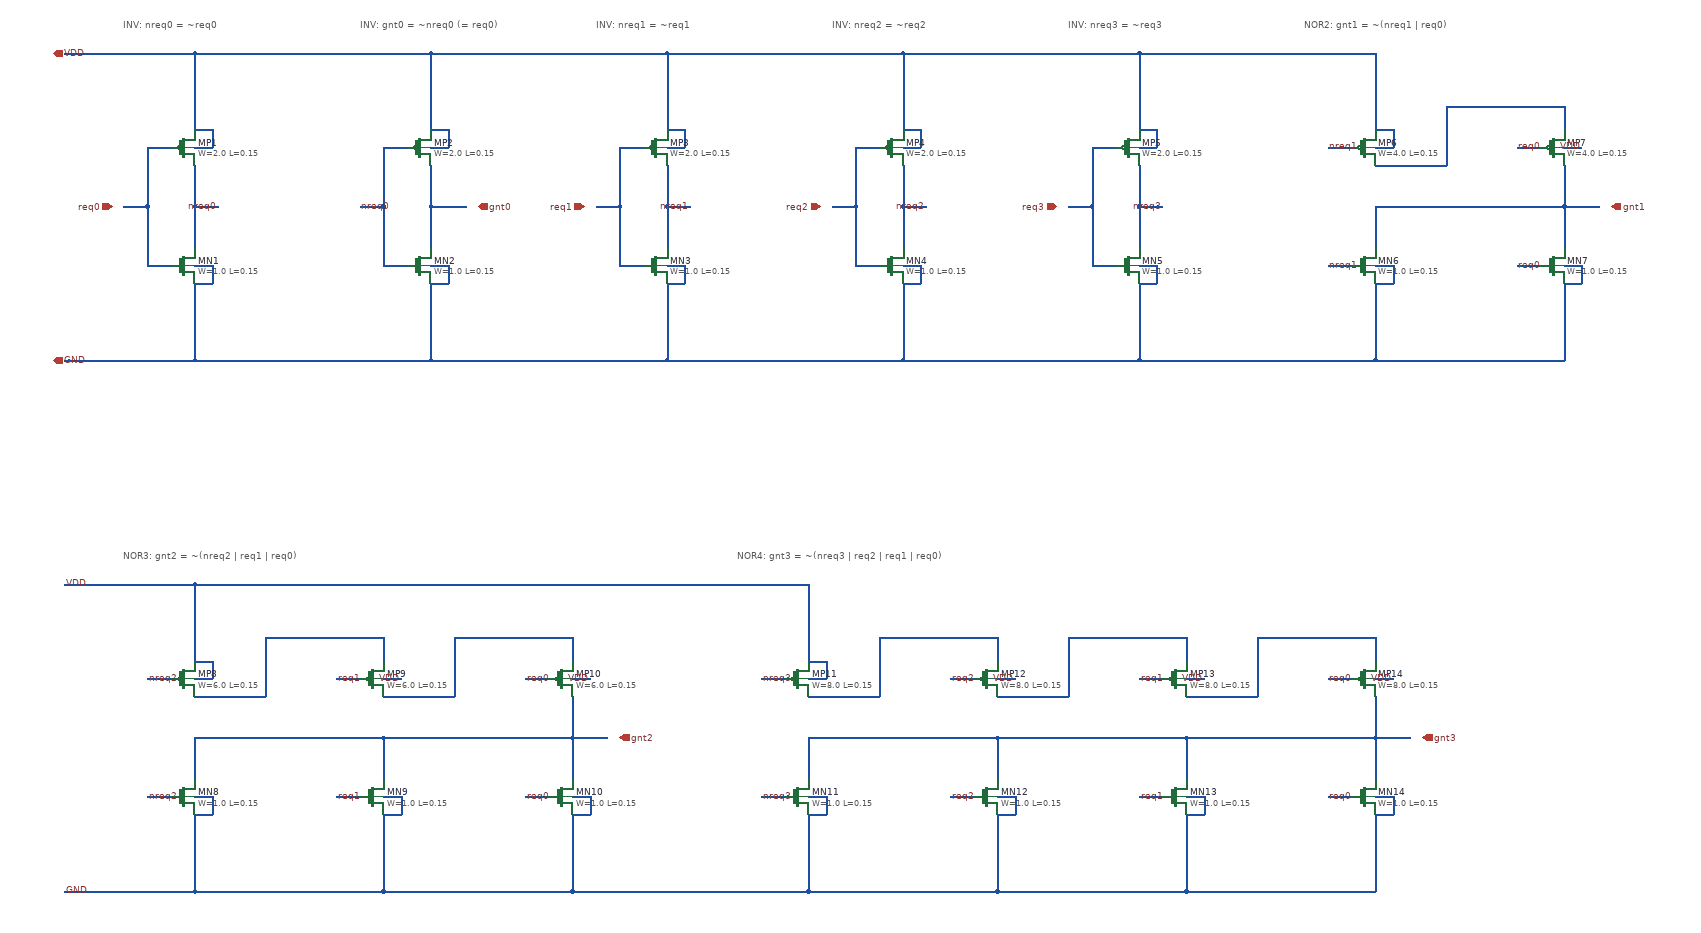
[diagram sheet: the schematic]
v {xschem version=3.4.5 file_version=1.2
}
G {}
K {}
V {}
S {}
E {}
N 180 -100 140 -100 {}
N 180 100 140 100 {}
N 140 -100 140 0 {}
N 140 0 140 100 {}
N 140 0 100 0 {}
N 220 -100 250 -100 {}
N 250 -100 250 -130 {}
N 250 -130 220 -130 {}
N 220 -130 220 -260 {}
N 220 -70 220 0 {}
N 220 100 250 100 {}
N 250 100 250 130 {}
N 250 130 220 130 {}
N 220 130 220 260 {}
N 220 70 220 0 {}
N 220 0 260 0 {}
N 580 -100 540 -100 {}
N 580 100 540 100 {}
N 540 -100 540 0 {}
N 540 0 540 100 {}
N 540 0 500 0 {}
N 620 -100 650 -100 {}
N 650 -100 650 -130 {}
N 650 -130 620 -130 {}
N 620 -130 620 -260 {}
N 620 -70 620 0 {}
N 620 100 650 100 {}
N 650 100 650 130 {}
N 650 130 620 130 {}
N 620 130 620 260 {}
N 620 70 620 0 {}
N 620 0 680 0 {}
N 980 -100 940 -100 {}
N 980 100 940 100 {}
N 940 -100 940 0 {}
N 940 0 940 100 {}
N 940 0 900 0 {}
N 1020 -100 1050 -100 {}
N 1050 -100 1050 -130 {}
N 1050 -130 1020 -130 {}
N 1020 -130 1020 -260 {}
N 1020 -70 1020 0 {}
N 1020 100 1050 100 {}
N 1050 100 1050 130 {}
N 1050 130 1020 130 {}
N 1020 130 1020 260 {}
N 1020 70 1020 0 {}
N 1020 0 1060 0 {}
N 1380 -100 1340 -100 {}
N 1380 100 1340 100 {}
N 1340 -100 1340 0 {}
N 1340 0 1340 100 {}
N 1340 0 1300 0 {}
N 1420 -100 1450 -100 {}
N 1450 -100 1450 -130 {}
N 1450 -130 1420 -130 {}
N 1420 -130 1420 -260 {}
N 1420 -70 1420 0 {}
N 1420 100 1450 100 {}
N 1450 100 1450 130 {}
N 1450 130 1420 130 {}
N 1420 130 1420 260 {}
N 1420 70 1420 0 {}
N 1420 0 1460 0 {}
N 1780 -100 1740 -100 {}
N 1780 100 1740 100 {}
N 1740 -100 1740 0 {}
N 1740 0 1740 100 {}
N 1740 0 1700 0 {}
N 1820 -100 1850 -100 {}
N 1850 -100 1850 -130 {}
N 1850 -130 1820 -130 {}
N 1820 -130 1820 -260 {}
N 1820 -70 1820 0 {}
N 1820 100 1850 100 {}
N 1850 100 1850 130 {}
N 1850 130 1820 130 {}
N 1820 130 1820 260 {}
N 1820 70 1820 0 {}
N 1820 0 1860 0 {}
N 2180 -100 2140 -100 {}
N 2180 100 2140 100 {}
N 2220 -100 2250 -100 {}
N 2250 -100 2250 -130 {}
N 2250 -130 2220 -130 {}
N 2220 -130 2220 -260 {}
N 2220 -70 2340 -70 {}
N 2340 -70 2340 -170 {}
N 2340 -170 2540 -170 {}
N 2540 -170 2540 -130 {}
N 2220 100 2250 100 {}
N 2250 100 2250 130 {}
N 2250 130 2220 130 {}
N 2220 130 2220 260 {}
N 2220 70 2220 0 {}
N 2500 -100 2460 -100 {}
N 2500 100 2460 100 {}
N 2540 -100 2570 -100 {}
N 2540 -70 2540 0 {}
N 2540 100 2570 100 {}
N 2570 100 2570 130 {}
N 2570 130 2540 130 {}
N 2540 130 2540 260 {}
N 2540 70 2540 0 {}
N 2220 0 2540 0 {}
N 2540 0 2600 0 {}
N 180 800 140 800 {}
N 180 1000 140 1000 {}
N 220 800 250 800 {}
N 250 800 250 770 {}
N 250 770 220 770 {}
N 220 770 220 640 {}
N 220 830 340 830 {}
N 340 830 340 730 {}
N 340 730 540 730 {}
N 540 730 540 770 {}
N 220 1000 250 1000 {}
N 250 1000 250 1030 {}
N 250 1030 220 1030 {}
N 220 1030 220 1160 {}
N 220 970 220 900 {}
N 500 800 460 800 {}
N 500 1000 460 1000 {}
N 540 800 570 800 {}
N 540 830 660 830 {}
N 660 830 660 730 {}
N 660 730 860 730 {}
N 860 730 860 770 {}
N 540 1000 570 1000 {}
N 570 1000 570 1030 {}
N 570 1030 540 1030 {}
N 540 1030 540 1160 {}
N 540 970 540 900 {}
N 220 900 540 900 {}
N 820 800 780 800 {}
N 820 1000 780 1000 {}
N 860 800 890 800 {}
N 860 830 860 900 {}
N 860 1000 890 1000 {}
N 890 1000 890 1030 {}
N 890 1030 860 1030 {}
N 860 1030 860 1160 {}
N 860 970 860 900 {}
N 540 900 860 900 {}
N 860 900 920 900 {}
N 1220 800 1180 800 {}
N 1220 1000 1180 1000 {}
N 1260 800 1290 800 {}
N 1290 800 1290 770 {}
N 1290 770 1260 770 {}
N 1260 770 1260 640 {}
N 1260 830 1380 830 {}
N 1380 830 1380 730 {}
N 1380 730 1580 730 {}
N 1580 730 1580 770 {}
N 1260 1000 1290 1000 {}
N 1290 1000 1290 1030 {}
N 1290 1030 1260 1030 {}
N 1260 1030 1260 1160 {}
N 1260 970 1260 900 {}
N 1540 800 1500 800 {}
N 1540 1000 1500 1000 {}
N 1580 800 1610 800 {}
N 1580 830 1700 830 {}
N 1700 830 1700 730 {}
N 1700 730 1900 730 {}
N 1900 730 1900 770 {}
N 1580 1000 1610 1000 {}
N 1610 1000 1610 1030 {}
N 1610 1030 1580 1030 {}
N 1580 1030 1580 1160 {}
N 1580 970 1580 900 {}
N 1260 900 1580 900 {}
N 1860 800 1820 800 {}
N 1860 1000 1820 1000 {}
N 1900 800 1930 800 {}
N 1900 830 2020 830 {}
N 2020 830 2020 730 {}
N 2020 730 2220 730 {}
N 2220 730 2220 770 {}
N 1900 1000 1930 1000 {}
N 1930 1000 1930 1030 {}
N 1930 1030 1900 1030 {}
N 1900 1030 1900 1160 {}
N 1900 970 1900 900 {}
N 1580 900 1900 900 {}
N 2180 800 2140 800 {}
N 2180 1000 2140 1000 {}
N 2220 800 2250 800 {}
N 2220 830 2220 900 {}
N 2220 1000 2250 1000 {}
N 2250 1000 2250 1030 {}
N 2250 1030 2220 1030 {}
N 2220 1030 2220 1160 {}
N 2220 970 2220 900 {}
N 1900 900 2220 900 {}
N 2220 900 2280 900 {}
N 0 -260 220 -260 {}
N 220 -260 620 -260 {}
N 620 -260 1020 -260 {}
N 1020 -260 1420 -260 {}
N 1420 -260 1820 -260 {}
N 1820 -260 2220 -260 {}
N 0 260 220 260 {}
N 220 260 620 260 {}
N 620 260 1020 260 {}
N 1020 260 1420 260 {}
N 1420 260 1820 260 {}
N 1820 260 2220 260 {}
N 2220 260 2540 260 {}
N 0 640 220 640 {}
N 220 640 1260 640 {}
N 0 1160 220 1160 {}
N 220 1160 540 1160 {}
N 540 1160 860 1160 {}
N 860 1160 1260 1160 {}
N 1260 1160 1580 1160 {}
N 1580 1160 1900 1160 {}
N 1900 1160 2220 1160 {}
C {sky130_fd_pr/pfet_01v8.sym} 200 -100 0 0 {name=MP1
L=0.15
W=2.0
nf=1
mult=1
ad="'int((nf+1)/2) * W/nf * 0.29'"
as="'int((nf+2)/2) * W/nf * 0.29'"
pd="'2*int((nf+1)/2) * (W/nf + 0.29)'"
ps="'2*int((nf+2)/2) * (W/nf + 0.29)'"
nrd="'0.29 / W'"
nrs="'0.29 / W'"
sa=0 sb=0 sd=0
model=pfet_01v8
spiceprefix=X
}
C {sky130_fd_pr/nfet_01v8.sym} 200 100 0 0 {name=MN1
L=0.15
W=1.0
nf=1
mult=1
ad="'int((nf+1)/2) * W/nf * 0.29'"
as="'int((nf+2)/2) * W/nf * 0.29'"
pd="'2*int((nf+1)/2) * (W/nf + 0.29)'"
ps="'2*int((nf+2)/2) * (W/nf + 0.29)'"
nrd="'0.29 / W'"
nrs="'0.29 / W'"
sa=0 sb=0 sd=0
model=nfet_01v8
spiceprefix=X
}
C {devices/ipin.sym} 80 0 0 0 {name=pi_req0 lab=req0}
C {devices/lab_pin.sym} 260 0 0 0 {name=l1 sig_type=std_logic lab=nreq0}
C {sky130_fd_pr/pfet_01v8.sym} 600 -100 0 0 {name=MP2
L=0.15
W=2.0
nf=1
mult=1
ad="'int((nf+1)/2) * W/nf * 0.29'"
as="'int((nf+2)/2) * W/nf * 0.29'"
pd="'2*int((nf+1)/2) * (W/nf + 0.29)'"
ps="'2*int((nf+2)/2) * (W/nf + 0.29)'"
nrd="'0.29 / W'"
nrs="'0.29 / W'"
sa=0 sb=0 sd=0
model=pfet_01v8
spiceprefix=X
}
C {sky130_fd_pr/nfet_01v8.sym} 600 100 0 0 {name=MN2
L=0.15
W=1.0
nf=1
mult=1
ad="'int((nf+1)/2) * W/nf * 0.29'"
as="'int((nf+2)/2) * W/nf * 0.29'"
pd="'2*int((nf+1)/2) * (W/nf + 0.29)'"
ps="'2*int((nf+2)/2) * (W/nf + 0.29)'"
nrd="'0.29 / W'"
nrs="'0.29 / W'"
sa=0 sb=0 sd=0
model=nfet_01v8
spiceprefix=X
}
C {devices/lab_pin.sym} 500 0 2 0 {name=l2 sig_type=std_logic lab=nreq0}
C {devices/opin.sym} 700 0 0 0 {name=po_gnt0 lab=gnt0}
C {sky130_fd_pr/pfet_01v8.sym} 1000 -100 0 0 {name=MP3
L=0.15
W=2.0
nf=1
mult=1
ad="'int((nf+1)/2) * W/nf * 0.29'"
as="'int((nf+2)/2) * W/nf * 0.29'"
pd="'2*int((nf+1)/2) * (W/nf + 0.29)'"
ps="'2*int((nf+2)/2) * (W/nf + 0.29)'"
nrd="'0.29 / W'"
nrs="'0.29 / W'"
sa=0 sb=0 sd=0
model=pfet_01v8
spiceprefix=X
}
C {sky130_fd_pr/nfet_01v8.sym} 1000 100 0 0 {name=MN3
L=0.15
W=1.0
nf=1
mult=1
ad="'int((nf+1)/2) * W/nf * 0.29'"
as="'int((nf+2)/2) * W/nf * 0.29'"
pd="'2*int((nf+1)/2) * (W/nf + 0.29)'"
ps="'2*int((nf+2)/2) * (W/nf + 0.29)'"
nrd="'0.29 / W'"
nrs="'0.29 / W'"
sa=0 sb=0 sd=0
model=nfet_01v8
spiceprefix=X
}
C {devices/ipin.sym} 880 0 0 0 {name=pi_req1 lab=req1}
C {devices/lab_pin.sym} 1060 0 0 0 {name=l3 sig_type=std_logic lab=nreq1}
C {sky130_fd_pr/pfet_01v8.sym} 1400 -100 0 0 {name=MP4
L=0.15
W=2.0
nf=1
mult=1
ad="'int((nf+1)/2) * W/nf * 0.29'"
as="'int((nf+2)/2) * W/nf * 0.29'"
pd="'2*int((nf+1)/2) * (W/nf + 0.29)'"
ps="'2*int((nf+2)/2) * (W/nf + 0.29)'"
nrd="'0.29 / W'"
nrs="'0.29 / W'"
sa=0 sb=0 sd=0
model=pfet_01v8
spiceprefix=X
}
C {sky130_fd_pr/nfet_01v8.sym} 1400 100 0 0 {name=MN4
L=0.15
W=1.0
nf=1
mult=1
ad="'int((nf+1)/2) * W/nf * 0.29'"
as="'int((nf+2)/2) * W/nf * 0.29'"
pd="'2*int((nf+1)/2) * (W/nf + 0.29)'"
ps="'2*int((nf+2)/2) * (W/nf + 0.29)'"
nrd="'0.29 / W'"
nrs="'0.29 / W'"
sa=0 sb=0 sd=0
model=nfet_01v8
spiceprefix=X
}
C {devices/ipin.sym} 1280 0 0 0 {name=pi_req2 lab=req2}
C {devices/lab_pin.sym} 1460 0 0 0 {name=l4 sig_type=std_logic lab=nreq2}
C {sky130_fd_pr/pfet_01v8.sym} 1800 -100 0 0 {name=MP5
L=0.15
W=2.0
nf=1
mult=1
ad="'int((nf+1)/2) * W/nf * 0.29'"
as="'int((nf+2)/2) * W/nf * 0.29'"
pd="'2*int((nf+1)/2) * (W/nf + 0.29)'"
ps="'2*int((nf+2)/2) * (W/nf + 0.29)'"
nrd="'0.29 / W'"
nrs="'0.29 / W'"
sa=0 sb=0 sd=0
model=pfet_01v8
spiceprefix=X
}
C {sky130_fd_pr/nfet_01v8.sym} 1800 100 0 0 {name=MN5
L=0.15
W=1.0
nf=1
mult=1
ad="'int((nf+1)/2) * W/nf * 0.29'"
as="'int((nf+2)/2) * W/nf * 0.29'"
pd="'2*int((nf+1)/2) * (W/nf + 0.29)'"
ps="'2*int((nf+2)/2) * (W/nf + 0.29)'"
nrd="'0.29 / W'"
nrs="'0.29 / W'"
sa=0 sb=0 sd=0
model=nfet_01v8
spiceprefix=X
}
C {devices/ipin.sym} 1680 0 0 0 {name=pi_req3 lab=req3}
C {devices/lab_pin.sym} 1860 0 0 0 {name=l5 sig_type=std_logic lab=nreq3}
C {sky130_fd_pr/pfet_01v8.sym} 2200 -100 0 0 {name=MP6
L=0.15
W=4.0
nf=1
mult=1
ad="'int((nf+1)/2) * W/nf * 0.29'"
as="'int((nf+2)/2) * W/nf * 0.29'"
pd="'2*int((nf+1)/2) * (W/nf + 0.29)'"
ps="'2*int((nf+2)/2) * (W/nf + 0.29)'"
nrd="'0.29 / W'"
nrs="'0.29 / W'"
sa=0 sb=0 sd=0
model=pfet_01v8
spiceprefix=X
}
C {sky130_fd_pr/nfet_01v8.sym} 2200 100 0 0 {name=MN6
L=0.15
W=1.0
nf=1
mult=1
ad="'int((nf+1)/2) * W/nf * 0.29'"
as="'int((nf+2)/2) * W/nf * 0.29'"
pd="'2*int((nf+1)/2) * (W/nf + 0.29)'"
ps="'2*int((nf+2)/2) * (W/nf + 0.29)'"
nrd="'0.29 / W'"
nrs="'0.29 / W'"
sa=0 sb=0 sd=0
model=nfet_01v8
spiceprefix=X
}
C {devices/lab_pin.sym} 2140 -100 2 0 {name=l6 sig_type=std_logic lab=nreq1}
C {devices/lab_pin.sym} 2140 100 2 0 {name=l7 sig_type=std_logic lab=nreq1}
C {sky130_fd_pr/pfet_01v8.sym} 2520 -100 0 0 {name=MP7
L=0.15
W=4.0
nf=1
mult=1
ad="'int((nf+1)/2) * W/nf * 0.29'"
as="'int((nf+2)/2) * W/nf * 0.29'"
pd="'2*int((nf+1)/2) * (W/nf + 0.29)'"
ps="'2*int((nf+2)/2) * (W/nf + 0.29)'"
nrd="'0.29 / W'"
nrs="'0.29 / W'"
sa=0 sb=0 sd=0
model=pfet_01v8
spiceprefix=X
}
C {sky130_fd_pr/nfet_01v8.sym} 2520 100 0 0 {name=MN7
L=0.15
W=1.0
nf=1
mult=1
ad="'int((nf+1)/2) * W/nf * 0.29'"
as="'int((nf+2)/2) * W/nf * 0.29'"
pd="'2*int((nf+1)/2) * (W/nf + 0.29)'"
ps="'2*int((nf+2)/2) * (W/nf + 0.29)'"
nrd="'0.29 / W'"
nrs="'0.29 / W'"
sa=0 sb=0 sd=0
model=nfet_01v8
spiceprefix=X
}
C {devices/lab_pin.sym} 2460 -100 2 0 {name=l8 sig_type=std_logic lab=req0}
C {devices/lab_pin.sym} 2460 100 2 0 {name=l9 sig_type=std_logic lab=req0}
C {devices/lab_pin.sym} 2570 -100 0 0 {name=l10 sig_type=std_logic lab=VDD}
C {devices/opin.sym} 2620 0 0 0 {name=po_gnt1 lab=gnt1}
C {sky130_fd_pr/pfet_01v8.sym} 200 800 0 0 {name=MP8
L=0.15
W=6.0
nf=1
mult=1
ad="'int((nf+1)/2) * W/nf * 0.29'"
as="'int((nf+2)/2) * W/nf * 0.29'"
pd="'2*int((nf+1)/2) * (W/nf + 0.29)'"
ps="'2*int((nf+2)/2) * (W/nf + 0.29)'"
nrd="'0.29 / W'"
nrs="'0.29 / W'"
sa=0 sb=0 sd=0
model=pfet_01v8
spiceprefix=X
}
C {sky130_fd_pr/nfet_01v8.sym} 200 1000 0 0 {name=MN8
L=0.15
W=1.0
nf=1
mult=1
ad="'int((nf+1)/2) * W/nf * 0.29'"
as="'int((nf+2)/2) * W/nf * 0.29'"
pd="'2*int((nf+1)/2) * (W/nf + 0.29)'"
ps="'2*int((nf+2)/2) * (W/nf + 0.29)'"
nrd="'0.29 / W'"
nrs="'0.29 / W'"
sa=0 sb=0 sd=0
model=nfet_01v8
spiceprefix=X
}
C {devices/lab_pin.sym} 140 800 2 0 {name=l11 sig_type=std_logic lab=nreq2}
C {devices/lab_pin.sym} 140 1000 2 0 {name=l12 sig_type=std_logic lab=nreq2}
C {sky130_fd_pr/pfet_01v8.sym} 520 800 0 0 {name=MP9
L=0.15
W=6.0
nf=1
mult=1
ad="'int((nf+1)/2) * W/nf * 0.29'"
as="'int((nf+2)/2) * W/nf * 0.29'"
pd="'2*int((nf+1)/2) * (W/nf + 0.29)'"
ps="'2*int((nf+2)/2) * (W/nf + 0.29)'"
nrd="'0.29 / W'"
nrs="'0.29 / W'"
sa=0 sb=0 sd=0
model=pfet_01v8
spiceprefix=X
}
C {sky130_fd_pr/nfet_01v8.sym} 520 1000 0 0 {name=MN9
L=0.15
W=1.0
nf=1
mult=1
ad="'int((nf+1)/2) * W/nf * 0.29'"
as="'int((nf+2)/2) * W/nf * 0.29'"
pd="'2*int((nf+1)/2) * (W/nf + 0.29)'"
ps="'2*int((nf+2)/2) * (W/nf + 0.29)'"
nrd="'0.29 / W'"
nrs="'0.29 / W'"
sa=0 sb=0 sd=0
model=nfet_01v8
spiceprefix=X
}
C {devices/lab_pin.sym} 460 800 2 0 {name=l13 sig_type=std_logic lab=req1}
C {devices/lab_pin.sym} 460 1000 2 0 {name=l14 sig_type=std_logic lab=req1}
C {devices/lab_pin.sym} 570 800 0 0 {name=l15 sig_type=std_logic lab=VDD}
C {sky130_fd_pr/pfet_01v8.sym} 840 800 0 0 {name=MP10
L=0.15
W=6.0
nf=1
mult=1
ad="'int((nf+1)/2) * W/nf * 0.29'"
as="'int((nf+2)/2) * W/nf * 0.29'"
pd="'2*int((nf+1)/2) * (W/nf + 0.29)'"
ps="'2*int((nf+2)/2) * (W/nf + 0.29)'"
nrd="'0.29 / W'"
nrs="'0.29 / W'"
sa=0 sb=0 sd=0
model=pfet_01v8
spiceprefix=X
}
C {sky130_fd_pr/nfet_01v8.sym} 840 1000 0 0 {name=MN10
L=0.15
W=1.0
nf=1
mult=1
ad="'int((nf+1)/2) * W/nf * 0.29'"
as="'int((nf+2)/2) * W/nf * 0.29'"
pd="'2*int((nf+1)/2) * (W/nf + 0.29)'"
ps="'2*int((nf+2)/2) * (W/nf + 0.29)'"
nrd="'0.29 / W'"
nrs="'0.29 / W'"
sa=0 sb=0 sd=0
model=nfet_01v8
spiceprefix=X
}
C {devices/lab_pin.sym} 780 800 2 0 {name=l16 sig_type=std_logic lab=req0}
C {devices/lab_pin.sym} 780 1000 2 0 {name=l17 sig_type=std_logic lab=req0}
C {devices/lab_pin.sym} 890 800 0 0 {name=l18 sig_type=std_logic lab=VDD}
C {devices/opin.sym} 940 900 0 0 {name=po_gnt2 lab=gnt2}
C {sky130_fd_pr/pfet_01v8.sym} 1240 800 0 0 {name=MP11
L=0.15
W=8.0
nf=1
mult=1
ad="'int((nf+1)/2) * W/nf * 0.29'"
as="'int((nf+2)/2) * W/nf * 0.29'"
pd="'2*int((nf+1)/2) * (W/nf + 0.29)'"
ps="'2*int((nf+2)/2) * (W/nf + 0.29)'"
nrd="'0.29 / W'"
nrs="'0.29 / W'"
sa=0 sb=0 sd=0
model=pfet_01v8
spiceprefix=X
}
C {sky130_fd_pr/nfet_01v8.sym} 1240 1000 0 0 {name=MN11
L=0.15
W=1.0
nf=1
mult=1
ad="'int((nf+1)/2) * W/nf * 0.29'"
as="'int((nf+2)/2) * W/nf * 0.29'"
pd="'2*int((nf+1)/2) * (W/nf + 0.29)'"
ps="'2*int((nf+2)/2) * (W/nf + 0.29)'"
nrd="'0.29 / W'"
nrs="'0.29 / W'"
sa=0 sb=0 sd=0
model=nfet_01v8
spiceprefix=X
}
C {devices/lab_pin.sym} 1180 800 2 0 {name=l19 sig_type=std_logic lab=nreq3}
C {devices/lab_pin.sym} 1180 1000 2 0 {name=l20 sig_type=std_logic lab=nreq3}
C {sky130_fd_pr/pfet_01v8.sym} 1560 800 0 0 {name=MP12
L=0.15
W=8.0
nf=1
mult=1
ad="'int((nf+1)/2) * W/nf * 0.29'"
as="'int((nf+2)/2) * W/nf * 0.29'"
pd="'2*int((nf+1)/2) * (W/nf + 0.29)'"
ps="'2*int((nf+2)/2) * (W/nf + 0.29)'"
nrd="'0.29 / W'"
nrs="'0.29 / W'"
sa=0 sb=0 sd=0
model=pfet_01v8
spiceprefix=X
}
C {sky130_fd_pr/nfet_01v8.sym} 1560 1000 0 0 {name=MN12
L=0.15
W=1.0
nf=1
mult=1
ad="'int((nf+1)/2) * W/nf * 0.29'"
as="'int((nf+2)/2) * W/nf * 0.29'"
pd="'2*int((nf+1)/2) * (W/nf + 0.29)'"
ps="'2*int((nf+2)/2) * (W/nf + 0.29)'"
nrd="'0.29 / W'"
nrs="'0.29 / W'"
sa=0 sb=0 sd=0
model=nfet_01v8
spiceprefix=X
}
C {devices/lab_pin.sym} 1500 800 2 0 {name=l21 sig_type=std_logic lab=req2}
C {devices/lab_pin.sym} 1500 1000 2 0 {name=l22 sig_type=std_logic lab=req2}
C {devices/lab_pin.sym} 1610 800 0 0 {name=l23 sig_type=std_logic lab=VDD}
C {sky130_fd_pr/pfet_01v8.sym} 1880 800 0 0 {name=MP13
L=0.15
W=8.0
nf=1
mult=1
ad="'int((nf+1)/2) * W/nf * 0.29'"
as="'int((nf+2)/2) * W/nf * 0.29'"
pd="'2*int((nf+1)/2) * (W/nf + 0.29)'"
ps="'2*int((nf+2)/2) * (W/nf + 0.29)'"
nrd="'0.29 / W'"
nrs="'0.29 / W'"
sa=0 sb=0 sd=0
model=pfet_01v8
spiceprefix=X
}
C {sky130_fd_pr/nfet_01v8.sym} 1880 1000 0 0 {name=MN13
L=0.15
W=1.0
nf=1
mult=1
ad="'int((nf+1)/2) * W/nf * 0.29'"
as="'int((nf+2)/2) * W/nf * 0.29'"
pd="'2*int((nf+1)/2) * (W/nf + 0.29)'"
ps="'2*int((nf+2)/2) * (W/nf + 0.29)'"
nrd="'0.29 / W'"
nrs="'0.29 / W'"
sa=0 sb=0 sd=0
model=nfet_01v8
spiceprefix=X
}
C {devices/lab_pin.sym} 1820 800 2 0 {name=l24 sig_type=std_logic lab=req1}
C {devices/lab_pin.sym} 1820 1000 2 0 {name=l25 sig_type=std_logic lab=req1}
C {devices/lab_pin.sym} 1930 800 0 0 {name=l26 sig_type=std_logic lab=VDD}
C {sky130_fd_pr/pfet_01v8.sym} 2200 800 0 0 {name=MP14
L=0.15
W=8.0
nf=1
mult=1
ad="'int((nf+1)/2) * W/nf * 0.29'"
as="'int((nf+2)/2) * W/nf * 0.29'"
pd="'2*int((nf+1)/2) * (W/nf + 0.29)'"
ps="'2*int((nf+2)/2) * (W/nf + 0.29)'"
nrd="'0.29 / W'"
nrs="'0.29 / W'"
sa=0 sb=0 sd=0
model=pfet_01v8
spiceprefix=X
}
C {sky130_fd_pr/nfet_01v8.sym} 2200 1000 0 0 {name=MN14
L=0.15
W=1.0
nf=1
mult=1
ad="'int((nf+1)/2) * W/nf * 0.29'"
as="'int((nf+2)/2) * W/nf * 0.29'"
pd="'2*int((nf+1)/2) * (W/nf + 0.29)'"
ps="'2*int((nf+2)/2) * (W/nf + 0.29)'"
nrd="'0.29 / W'"
nrs="'0.29 / W'"
sa=0 sb=0 sd=0
model=nfet_01v8
spiceprefix=X
}
C {devices/lab_pin.sym} 2140 800 2 0 {name=l27 sig_type=std_logic lab=req0}
C {devices/lab_pin.sym} 2140 1000 2 0 {name=l28 sig_type=std_logic lab=req0}
C {devices/lab_pin.sym} 2250 800 0 0 {name=l29 sig_type=std_logic lab=VDD}
C {devices/opin.sym} 2300 900 0 0 {name=po_gnt3 lab=gnt3}
C {devices/iopin.sym} -20 -260 0 1 {name=pv lab=VDD}
C {devices/iopin.sym} -20 260 0 1 {name=pg lab=GND}
C {devices/lab_pin.sym} 0 640 2 0 {name=l30 sig_type=std_logic lab=VDD}
C {devices/lab_pin.sym} 0 1160 2 0 {name=l31 sig_type=std_logic lab=GND}
T {INV: nreq0 = ~req0} 100 -320 0 0 0.4 0.4 {}
T {INV: gnt0 = ~nreq0 (= req0)} 500 -320 0 0 0.4 0.4 {}
T {INV: nreq1 = ~req1} 900 -320 0 0 0.4 0.4 {}
T {INV: nreq2 = ~req2} 1300 -320 0 0 0.4 0.4 {}
T {INV: nreq3 = ~req3} 1700 -320 0 0 0.4 0.4 {}
T {NOR2: gnt1 = ~(nreq1 | req0)} 2100 -320 0 0 0.4 0.4 {}
T {NOR3: gnt2 = ~(nreq2 | req1 | req0)} 100 580 0 0 0.4 0.4 {}
T {NOR4: gnt3 = ~(nreq3 | req2 | req1 | req0)} 1140 580 0 0 0.4 0.4 {}
